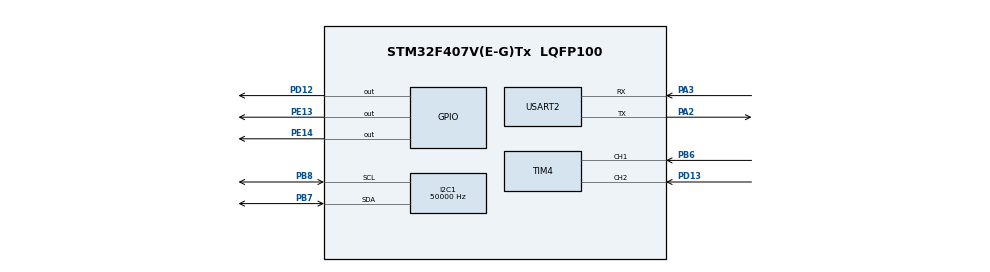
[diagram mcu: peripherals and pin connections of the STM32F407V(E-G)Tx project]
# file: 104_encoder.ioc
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I2C1.ClockSpeed=50000
Mcu.Family=STM32F4
Mcu.Name=STM32F407V(E-G)Tx
Mcu.Package=LQFP100
NVIC.I2C1_ER_IRQn=true\:0\:0\:false\:true\:true\:3\:true\:true\:true
NVIC.I2C1_EV_IRQn=true\:0\:0\:false\:true\:true\:2\:true\:true\:true
NVIC.PriorityGroup=NVIC_PRIORITYGROUP_4
NVIC.TIM2_IRQn=true\:0\:0\:false\:true\:true\:1\:true\:true\:true
NVIC.TIM3_IRQn=true\:0\:0\:false\:true\:true\:6\:true\:true\:true
NVIC.TIM4_IRQn=true\:0\:0\:false\:true\:true\:5\:true\:true\:true
NVIC.USART2_IRQn=true\:0\:0\:false\:true\:true\:4\:true\:true\:true
PA13.Mode=Serial_Wire
PA13.Signal=SYS_JTMS-SWDIO
PA14.Mode=Serial_Wire
PA14.Signal=SYS_JTCK-SWCLK
PA2.Mode=Asynchronous
PA2.Signal=USART2_TX
PA3.Mode=Asynchronous
PA3.Signal=USART2_RX
PB6.Signal=S_TIM4_CH1
PB7.Mode=I2C
PB7.Signal=I2C1_SDA
PB8.Mode=I2C
PB8.Signal=I2C1_SCL
PD12.Signal=GPIO_Output
PD13.Signal=S_TIM4_CH2
PE13.Signal=GPIO_Output
PE14.Signal=GPIO_Output
ProjectManager.HeapSize=0x200
ProjectManager.StackSize=0x400
ProjectManager.TargetToolchain=STM32CubeIDE
RCC.48MHZClocksFreq_Value=42000000
RCC.AHBFreq_Value=16000000
RCC.APB1CLKDivider=RCC_HCLK_DIV2
RCC.APB1Freq_Value=8000000
RCC.APB1TimFreq_Value=16000000
RCC.APB2Freq_Value=16000000
RCC.APB2TimFreq_Value=16000000
RCC.CortexFreq_Value=16000000
RCC.HCLKFreq_Value=16000000
RCC.HSE_VALUE=25000000
RCC.HSI_VALUE=16000000
RCC.LSE_VALUE=32768
RCC.PLLN=168
RCC.SYSCLKFreq_VALUE=16000000
RCC.VCOOutputFreq_Value=168000000
SH.S_TIM4_CH1.0=TIM4_CH1,Encoder_Interface
SH.S_TIM4_CH2.0=TIM4_CH2,Encoder_Interface
TIM2.Period=250-1
TIM2.Prescaler=8400-1
TIM3.Period=1000-1
TIM3.Prescaler=8400-1
TIM4.IC1Filter=0xf
TIM4.IC2Filter=0xf
USART2.VirtualMode=VM_ASYNC
VP_TIM2_VS_ClockSourceINT.Mode=Internal
VP_TIM3_VS_ClockSourceINT.Mode=Internal
board=custom

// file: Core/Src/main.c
/* USER CODE BEGIN Header */
/**
  ******************************************************************************
  * @file           : main.c
  * @brief          : Main program body
  ******************************************************************************
  * @attention
  *
  * Copyright (c) 2025 STMicroelectronics.
  * All rights reserved.
  *
  * This software is licensed under terms that can be found in the LICENSE file
  * in the root directory of this software component.
  * If no LICENSE file comes with this software, it is provided AS-IS.
  *
  ******************************************************************************
  */
/* USER CODE END Header */
#include "main.h"
#include "kalman.h"
#include "mpu6050.h"
#include <stdio.h>
#include <math.h>

I2C_HandleTypeDef hi2c1;

TIM_HandleTypeDef htim2;
TIM_HandleTypeDef htim3;
TIM_HandleTypeDef htim4;

UART_HandleTypeDef huart2;

/* USER CODE BEGIN PV */
char f_imu_read = 0; // Flag to indicate when to read IMU data
char f_uart_send = 0; // Flag to indicate when to send data over UART
// Serial data buffer
uint8_t rxData[1];

int16_t ax, ay, az; // Accelerometer raw data
int16_t gx, gy, gz; // Gyroscope raw data
int16_t pitch, roll, yaw; // Filtered orientation angles (scaled)

volatile int32_t encoder_count = 0;  // variable holds encoder value

/* USER CODE END PV */

void SystemClock_Config(void);
static void MX_GPIO_Init(void);
static void MX_I2C1_Init(void);
static void MX_TIM2_Init(void);
static void MX_TIM3_Init(void);
static void MX_USART2_UART_Init(void);
static void MX_TIM4_Init(void);
static void MX_NVIC_Init(void);
/* USER CODE BEGIN PFP */
void Send_IMU_Data(int16_t* ax, int16_t* ay, int16_t* az, int16_t* gx, int16_t* gy, int16_t* gz, int16_t* pitch, int16_t* roll, int16_t* yaw); // Sends all IMU data via UART
void Compute_Orientation_Kalman(); // Computes pitch, roll, and yaw using a Kalman filter
/* USER CODE END PFP */

/* USER CODE BEGIN 0 */
// Redirects printf() to USART2 for debugging
int _write(int file, char *ptr, int len) {
    HAL_UART_Transmit(&huart2, (uint8_t*) ptr, len, HAL_MAX_DELAY);
    return len;
}
/* USER CODE END 0 */

int main(void)
{

  /* MCU Configuration--------------------------------------------------------*/

  /* Reset of all peripherals, Initializes the Flash interface and the Systick. */
  HAL_Init();

  /* Configure the system clock */
  SystemClock_Config();

  /* Initialize all configured peripherals */
  MX_GPIO_Init();
  MX_I2C1_Init();
  MX_TIM2_Init();
  MX_TIM3_Init();
  MX_USART2_UART_Init();
  MX_TIM4_Init();

  /* Initialize interrupts */
  MX_NVIC_Init();
  /* USER CODE BEGIN 2 */
  HAL_TIM_Base_Start_IT(&htim2);
  HAL_TIM_Base_Start_IT(&htim3);
  MPU6050_Init();
  Kalman_Init(&kalman_pitch);
  Kalman_Init(&kalman_roll);
  Kalman_Init(&kalman_yaw);

  HAL_UART_Receive_IT(&huart2, rxData, 1); // ?��?��?��?�� 기반 ?��?�� ?��?��
  HAL_TIM_Encoder_Start(&htim4, TIM_CHANNEL_ALL);  // 엔코더 인터페이스 시작
  /* USER CODE END 2 */

  /* Infinite loop */
  /* USER CODE BEGIN WHILE */
  while (1)
  {
	  if(f_imu_read == 1){
		  MPU6050_ReadAccel(&ax, &ay, &az);
		  MPU6050_ReadGyro(&gx, &gy, &gz);
		  HAL_GPIO_WritePin(GPIOD, GPIO_PIN_12, 1);
		  Compute_Orientation_Kalman();
		  //HAL_GPIO_WritePin(GPIOD, GPIO_PIN_12, 0);
		  //printf("Accel X: %d Y: %d Z: %d Gyro: X: %d, Y: %d, Z: %d \r\n", ax, ay, az, gx, gy, gz);
		  //Send_IMU_Data(&ax, &ay, &az, &gx, &gy, &gz);
		  f_imu_read = 0;
	  }
	  if(f_uart_send == 1){
		  //printf("Pitch %d Roll %d Yaw %d \r\n", pitch, roll, yaw);
		  Send_IMU_Data(&ax, &ay, &az, &gx, &gy, &gz, &pitch, &roll, &yaw);
		  encoder_count = (int32_t)__HAL_TIM_GET_COUNTER(&htim4);
		  f_uart_send = 0;
	  }
    /* USER CODE END WHILE */

  }
}

void SystemClock_Config(void)
{
  RCC_OscInitTypeDef RCC_OscInitStruct = {0};
  RCC_ClkInitTypeDef RCC_ClkInitStruct = {0};

  /** Configure the main internal regulator output voltage
  */
  __HAL_RCC_PWR_CLK_ENABLE();
  __HAL_PWR_VOLTAGESCALING_CONFIG(PWR_REGULATOR_VOLTAGE_SCALE1);

  /** Initializes the RCC Oscillators according to the specified parameters
  * in the RCC_OscInitTypeDef structure.
  */
  RCC_OscInitStruct.OscillatorType = RCC_OSCILLATORTYPE_HSI;
  RCC_OscInitStruct.HSIState = RCC_HSI_ON;
  RCC_OscInitStruct.HSICalibrationValue = RCC_HSICALIBRATION_DEFAULT;
  RCC_OscInitStruct.PLL.PLLState = RCC_PLL_ON;
  RCC_OscInitStruct.PLL.PLLSource = RCC_PLLSOURCE_HSI;
  RCC_OscInitStruct.PLL.PLLM = 16;
  RCC_OscInitStruct.PLL.PLLN = 168;
  RCC_OscInitStruct.PLL.PLLP = RCC_PLLP_DIV2;
  RCC_OscInitStruct.PLL.PLLQ = 4;
  if (HAL_RCC_OscConfig(&RCC_OscInitStruct) != HAL_OK)
  {
    Error_Handler();
  }

  /** Initializes the CPU, AHB and APB buses clocks
  */
  RCC_ClkInitStruct.ClockType = RCC_CLOCKTYPE_HCLK|RCC_CLOCKTYPE_SYSCLK
                              |RCC_CLOCKTYPE_PCLK1|RCC_CLOCKTYPE_PCLK2;
  RCC_ClkInitStruct.SYSCLKSource = RCC_SYSCLKSOURCE_PLLCLK;
  RCC_ClkInitStruct.AHBCLKDivider = RCC_SYSCLK_DIV1;
  RCC_ClkInitStruct.APB1CLKDivider = RCC_HCLK_DIV2;
  RCC_ClkInitStruct.APB2CLKDivider = RCC_HCLK_DIV1;

  if (HAL_RCC_ClockConfig(&RCC_ClkInitStruct, FLASH_LATENCY_2) != HAL_OK)
  {
    Error_Handler();
  }
}

/**
  * @brief NVIC Configuration.
  * @retval None
  */
static void MX_NVIC_Init(void)
{
  /* TIM2_IRQn interrupt configuration */
  HAL_NVIC_SetPriority(TIM2_IRQn, 0, 0);
  HAL_NVIC_EnableIRQ(TIM2_IRQn);
  /* I2C1_EV_IRQn interrupt configuration */
  HAL_NVIC_SetPriority(I2C1_EV_IRQn, 0, 0);
  HAL_NVIC_EnableIRQ(I2C1_EV_IRQn);
  /* I2C1_ER_IRQn interrupt configuration */
  HAL_NVIC_SetPriority(I2C1_ER_IRQn, 0, 0);
  HAL_NVIC_EnableIRQ(I2C1_ER_IRQn);
  /* USART2_IRQn interrupt configuration */
  HAL_NVIC_SetPriority(USART2_IRQn, 0, 0);
  HAL_NVIC_EnableIRQ(USART2_IRQn);
  /* TIM4_IRQn interrupt configuration */
  HAL_NVIC_SetPriority(TIM4_IRQn, 0, 0);
  HAL_NVIC_EnableIRQ(TIM4_IRQn);
  /* TIM3_IRQn interrupt configuration */
  HAL_NVIC_SetPriority(TIM3_IRQn, 0, 0);
  HAL_NVIC_EnableIRQ(TIM3_IRQn);
}

static void MX_I2C1_Init(void)
{

  hi2c1.Instance = I2C1;
  hi2c1.Init.ClockSpeed = 50000;
  hi2c1.Init.DutyCycle = I2C_DUTYCYCLE_2;
  hi2c1.Init.OwnAddress1 = 0;
  hi2c1.Init.AddressingMode = I2C_ADDRESSINGMODE_7BIT;
  hi2c1.Init.DualAddressMode = I2C_DUALADDRESS_DISABLE;
  hi2c1.Init.OwnAddress2 = 0;
  hi2c1.Init.GeneralCallMode = I2C_GENERALCALL_DISABLE;
  hi2c1.Init.NoStretchMode = I2C_NOSTRETCH_DISABLE;
  if (HAL_I2C_Init(&hi2c1) != HAL_OK)
  {
    Error_Handler();
  }

}

static void MX_TIM2_Init(void)
{

  TIM_ClockConfigTypeDef sClockSourceConfig = {0};
  TIM_MasterConfigTypeDef sMasterConfig = {0};

  htim2.Instance = TIM2;
  htim2.Init.Prescaler = 8400-1;
  htim2.Init.CounterMode = TIM_COUNTERMODE_UP;
  htim2.Init.Period = 250-1;
  htim2.Init.ClockDivision = TIM_CLOCKDIVISION_DIV1;
  htim2.Init.AutoReloadPreload = TIM_AUTORELOAD_PRELOAD_DISABLE;
  if (HAL_TIM_Base_Init(&htim2) != HAL_OK)
  {
    Error_Handler();
  }
  sClockSourceConfig.ClockSource = TIM_CLOCKSOURCE_INTERNAL;
  if (HAL_TIM_ConfigClockSource(&htim2, &sClockSourceConfig) != HAL_OK)
  {
    Error_Handler();
  }
  sMasterConfig.MasterOutputTrigger = TIM_TRGO_RESET;
  sMasterConfig.MasterSlaveMode = TIM_MASTERSLAVEMODE_DISABLE;
  if (HAL_TIMEx_MasterConfigSynchronization(&htim2, &sMasterConfig) != HAL_OK)
  {
    Error_Handler();
  }

}

static void MX_TIM3_Init(void)
{

  TIM_ClockConfigTypeDef sClockSourceConfig = {0};
  TIM_MasterConfigTypeDef sMasterConfig = {0};

  htim3.Instance = TIM3;
  htim3.Init.Prescaler = 8400-1;
  htim3.Init.CounterMode = TIM_COUNTERMODE_UP;
  htim3.Init.Period = 1000-1;
  htim3.Init.ClockDivision = TIM_CLOCKDIVISION_DIV1;
  htim3.Init.AutoReloadPreload = TIM_AUTORELOAD_PRELOAD_DISABLE;
  if (HAL_TIM_Base_Init(&htim3) != HAL_OK)
  {
    Error_Handler();
  }
  sClockSourceConfig.ClockSource = TIM_CLOCKSOURCE_INTERNAL;
  if (HAL_TIM_ConfigClockSource(&htim3, &sClockSourceConfig) != HAL_OK)
  {
    Error_Handler();
  }
  sMasterConfig.MasterOutputTrigger = TIM_TRGO_RESET;
  sMasterConfig.MasterSlaveMode = TIM_MASTERSLAVEMODE_DISABLE;
  if (HAL_TIMEx_MasterConfigSynchronization(&htim3, &sMasterConfig) != HAL_OK)
  {
    Error_Handler();
  }

}

static void MX_TIM4_Init(void)
{

  TIM_Encoder_InitTypeDef sConfig = {0};
  TIM_MasterConfigTypeDef sMasterConfig = {0};

  htim4.Instance = TIM4;
  htim4.Init.Prescaler = 0;
  htim4.Init.CounterMode = TIM_COUNTERMODE_UP;
  htim4.Init.Period = 65535;
  htim4.Init.ClockDivision = TIM_CLOCKDIVISION_DIV1;
  htim4.Init.AutoReloadPreload = TIM_AUTORELOAD_PRELOAD_DISABLE;
  sConfig.EncoderMode = TIM_ENCODERMODE_TI1;
  sConfig.IC1Polarity = TIM_ICPOLARITY_RISING;
  sConfig.IC1Selection = TIM_ICSELECTION_DIRECTTI;
  sConfig.IC1Prescaler = TIM_ICPSC_DIV1;
  sConfig.IC1Filter = 0xf;
  sConfig.IC2Polarity = TIM_ICPOLARITY_RISING;
  sConfig.IC2Selection = TIM_ICSELECTION_DIRECTTI;
  sConfig.IC2Prescaler = TIM_ICPSC_DIV1;
  sConfig.IC2Filter = 0xf;
  if (HAL_TIM_Encoder_Init(&htim4, &sConfig) != HAL_OK)
  {
    Error_Handler();
  }
  sMasterConfig.MasterOutputTrigger = TIM_TRGO_RESET;
  sMasterConfig.MasterSlaveMode = TIM_MASTERSLAVEMODE_DISABLE;
  if (HAL_TIMEx_MasterConfigSynchronization(&htim4, &sMasterConfig) != HAL_OK)
  {
    Error_Handler();
  }

}

static void MX_USART2_UART_Init(void)
{

  huart2.Instance = USART2;
  huart2.Init.BaudRate = 115200;
  huart2.Init.WordLength = UART_WORDLENGTH_8B;
  huart2.Init.StopBits = UART_STOPBITS_1;
  huart2.Init.Parity = UART_PARITY_NONE;
  huart2.Init.Mode = UART_MODE_TX_RX;
  huart2.Init.HwFlowCtl = UART_HWCONTROL_NONE;
  huart2.Init.OverSampling = UART_OVERSAMPLING_16;
  if (HAL_UART_Init(&huart2) != HAL_OK)
  {
    Error_Handler();
  }

}

static void MX_GPIO_Init(void)
{
  GPIO_InitTypeDef GPIO_InitStruct = {0};

  /* GPIO Ports Clock Enable */
  __HAL_RCC_GPIOA_CLK_ENABLE();
  __HAL_RCC_GPIOE_CLK_ENABLE();
  __HAL_RCC_GPIOD_CLK_ENABLE();
  __HAL_RCC_GPIOB_CLK_ENABLE();

  /*Configure GPIO pin Output Level */
  HAL_GPIO_WritePin(GPIOE, GPIO_PIN_13|GPIO_PIN_14, GPIO_PIN_RESET);

  /*Configure GPIO pin Output Level */
  HAL_GPIO_WritePin(GPIOD, GPIO_PIN_12|GPIO_PIN_14, GPIO_PIN_RESET);

  /*Configure GPIO pins : PE13 PE14 */
  GPIO_InitStruct.Pin = GPIO_PIN_13|GPIO_PIN_14;
  GPIO_InitStruct.Mode = GPIO_MODE_OUTPUT_PP;
  GPIO_InitStruct.Pull = GPIO_NOPULL;
  GPIO_InitStruct.Speed = GPIO_SPEED_FREQ_LOW;
  HAL_GPIO_Init(GPIOE, &GPIO_InitStruct);

  /*Configure GPIO pins : PD12 PD14 */
  GPIO_InitStruct.Pin = GPIO_PIN_12|GPIO_PIN_14;
  GPIO_InitStruct.Mode = GPIO_MODE_OUTPUT_PP;
  GPIO_InitStruct.Pull = GPIO_NOPULL;
  GPIO_InitStruct.Speed = GPIO_SPEED_FREQ_LOW;
  HAL_GPIO_Init(GPIOD, &GPIO_InitStruct);

}

/* USER CODE BEGIN 4 */
void HAL_TIM_PeriodElapsedCallback(TIM_HandleTypeDef *htim) {
    if (htim->Instance == TIM2) {
    	HAL_GPIO_TogglePin(GPIOD, GPIO_PIN_12);
        f_imu_read = 1;
    }else if(htim->Instance == TIM3){
    	//HAL_GPIO_TogglePin(GPIOD, GPIO_PIN_12);
    	f_uart_send = 1;
    }
}

void Send_IMU_Data(int16_t* ax, int16_t* ay, int16_t* az, int16_t* gx, int16_t* gy, int16_t* gz, int16_t* pitch, int16_t* roll, int16_t* yaw) {

    uint8_t tx_buffer[18];

    // 16비트 ?��?���???????? 바이?�� 배열�???????? �?????????�� (Little Endian)
    tx_buffer[0] = *ax & 0xFF;
    tx_buffer[1] = (*ax >> 8) & 0xFF;
    tx_buffer[2] = *ay & 0xFF;
    tx_buffer[3] = (*ay >> 8) & 0xFF;
    tx_buffer[4] = *az & 0xFF;
    tx_buffer[5] = (*az >> 8) & 0xFF;
    tx_buffer[6] = *gx & 0xFF;
    tx_buffer[7] = (*gx >> 8) & 0xFF;
    tx_buffer[8] = *gy & 0xFF;
    tx_buffer[9] = (*gy >> 8) & 0xFF;
    tx_buffer[10] = *gz & 0xFF;
    tx_buffer[11] = (*gz >> 8) & 0xFF;
    tx_buffer[12] = *pitch & 0xFF;
    tx_buffer[13] = (*pitch >> 8) & 0xFF;
    tx_buffer[14] = *roll & 0xFF;
    tx_buffer[15] = (*roll >> 8) & 0xFF;
    tx_buffer[16] = *yaw & 0xFF;
    tx_buffer[17] = (*yaw >> 8) & 0xFF;

    // UART ?��?��
    HAL_UART_Transmit(&huart2, tx_buffer, 18, 100);
}

void Compute_Orientation_Kalman() {
    // �??????��?���????? 기반 pitch, roll 계산
    float acc_pitch = atan2(-ax, sqrt(ay * ay + az * az)) * 57.2958;
    float acc_roll  = atan2(ay, az) * 57.2958;

    // ?��?��로스코프 값을 deg/s ?��?���????? �??????��
    float gx_dps = gx / 131.0;
    float gy_dps = gy / 131.0;
    float gz_dps = gz / 131.0;

    // 칼만 ?��?�� ?��?��
    float pitch_f = Kalman_Update(&kalman_pitch, acc_pitch, gy_dps, dt);
    float roll_f  = Kalman_Update(&kalman_roll, acc_roll, gx_dps, dt);
    float yaw_f   = Kalman_Update(&kalman_yaw, yaw_f, gz_dps, dt);

    // float -> int �??????��
    pitch = (int16_t)(pitch_f * 100);
    roll  = (int16_t)(roll_f * 100);
    yaw   = (int16_t)(yaw_f * 100);
}

void HAL_UART_RxCpltCallback(UART_HandleTypeDef *huart) {
    if (huart->Instance == USART2) {
        if(rxData[0] == 'a'){
        	HAL_GPIO_WritePin(GPIOE, GPIO_PIN_13, 0);
        	HAL_GPIO_WritePin(GPIOE, GPIO_PIN_14, 0);
        }else if(rxData[0] == 'b'){
        	HAL_GPIO_WritePin(GPIOE, GPIO_PIN_13, 0);
        	HAL_GPIO_WritePin(GPIOE, GPIO_PIN_14, 1);
        }
    }
    HAL_UART_Receive_IT(&huart2, rxData, 1); // ?��?�� ?��?�� ?��?��
}

/* USER CODE END 4 */

void Error_Handler(void)
{
  __disable_irq();
  while (1)
  {
  }
}
